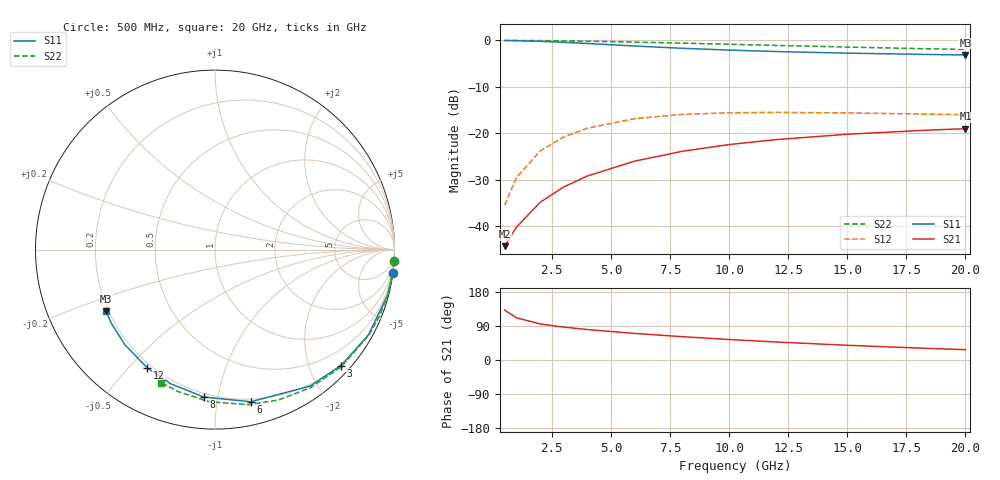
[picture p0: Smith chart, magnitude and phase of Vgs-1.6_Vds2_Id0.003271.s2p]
# Hz S RI R 50
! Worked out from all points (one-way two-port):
!   12 points, 500 MHz to 20 GHz, reference 50 ohm
!   highest |S21| = -19.00 dB at 20 GHz (marker M1); lowest = -44.3 dB at 500 MHz (marker M2)
!   lowest |S11| = -3.1 dB at 20 GHz (marker M3), VSWR 5.62, Z = 9.49 - j12.7 ohm
!   |S11| at or under -10 dB: nowhere
!   |S22| runs from -1.9 to 0.0 dB; largest |S21 - S12| = 0.12
!   S11 on the Smith chart (normalised r, x): 500 MHz: 0, -15; 3 GHz: 0.18, -2.55; 6 GHz: 0.18, -1.25; 8 GHz: 0.18, -0.91; 12 GHz: 0.18, -0.56; 20 GHz: 0.19, -0.25
5e8  0.9902 -0.129  -0.00405 0.00456  0.0016 0.0168  0.9974 -0.0643
1e9  0.9613 -0.2537  -0.00357 0.00909  0.0063 0.0328  0.9902 -0.1282
2e9  0.8543 -0.4759  -0.00164 0.018  0.0235 0.0599  0.9622 -0.2525
3e9  0.702 -0.6464  0.0015 0.0264  0.0474 0.0781  0.9173 -0.3692
4e9  0.5295 -0.7605  0.00578 0.0342  0.0734 0.0866  0.8576 -0.476
6e9  0.1991 -0.8479  0.017 0.0472  0.1187 0.0813  0.7062 -0.6505
8e9  -0.0614 -0.8214  0.0304 0.0562  0.1477 0.0607  0.5312 -0.7701
1e10  -0.2479 -0.7471  0.0444 0.0613  0.1622 0.0374  0.3534 -0.838
1.2e10  -0.3779 -0.6588  0.0579 0.0631  0.1672 0.0164  0.1858 -0.864
1.5e10  -0.503 -0.5288  0.0761 0.0613  0.1656 -0.00782  -0.0324 -0.8475
1.8e10  -0.5763 -0.4127  0.0912 0.0561  0.1597 -0.0245  -0.2065 -0.7906
2e10  -0.6074 -0.3438  0.0998 0.0515  0.1553 -0.0327  -0.3 -0.7406
